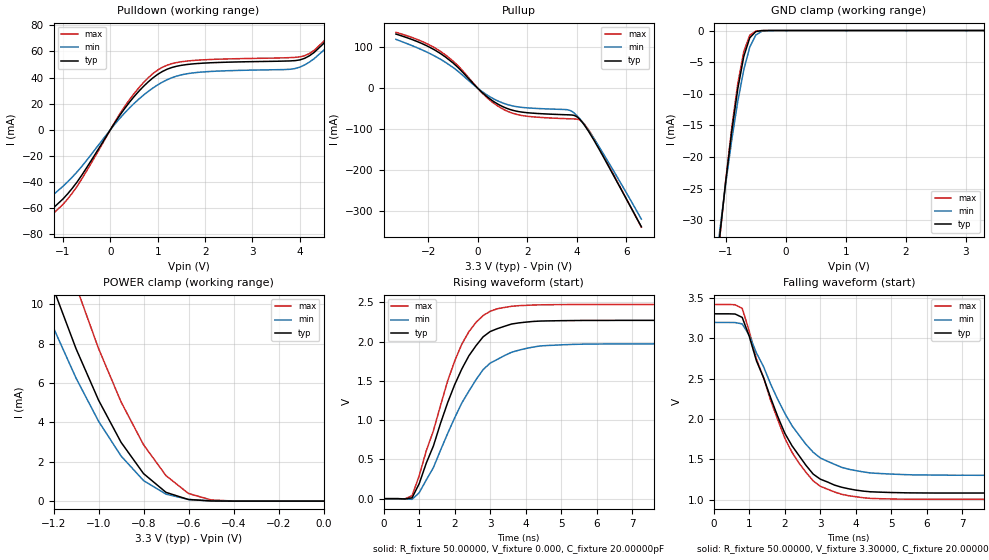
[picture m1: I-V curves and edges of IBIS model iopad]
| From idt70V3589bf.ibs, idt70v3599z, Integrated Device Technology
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|in   NC   NC
|oe   NC   NC
|   Model iopad
[Model]   iopad
Model_type   I/O
Polarity   Non-Inverting
Enable   Active-Low
Vinl =  0.80000V
Vinh =  2.00000V
Vmeas =  1.50000V
C_comp   4.50000pF   NA   NA
[Temperature Range]   25.00000   100.00000   0.000
[Voltage Range]   3.30000V   3.15000V   3.45000V
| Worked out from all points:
|   slope of the pulldown table from 0 to 0.495 V, typ, clamps not added: 19.7 ohm
|   slope of the pullup table from 0 to 0.495 V, typ, clamps not added: 18.9 ohm
|   GND clamp passes 1 mA (typ) near -0.58 V on its own axis
|   POWER clamp passes 1 mA (typ) near -0.76 V on its own axis
|   rising waveform, R_fixture 50.00000, V_fixture 0.000, C_fixture 20.00000pF: 20-80 % time 1.19ns typ, 1.3ns min, 1.09ns max; typ from 0 V to 2.27 V
|   falling waveform, R_fixture 50.00000, V_fixture 3.30000, C_fixture 20.00000pF: 20-80 % time 1.32ns typ, 1.4ns min, 1.26ns max; typ from 3.3 V to 1.08 V
[Pulldown]
| voltage   I(typ)   I(min)   I(max)
-3.3V     -84.5mA    -82mA      -85.8mA
-2.1V     -78mA      -70.6mA    -80.7mA
-1.3V     -63.18mA   -52.81mA   -67.45mA
-700mV    -39.93mA   -32.22mA   -43.24mA
500mV     25.36mA    20.13mA    27.67mA
1.2V      46.44mA    38.37mA    49.52mA
1.8V      50.66mA    43.81mA    53.24mA
4V        53.54mA    47.99mA    55.87mA
4.5V      66.02mA    60.79mA    67.62mA
4.7V      75.09mA    68.69mA    77.1mA
4.9V      86.42mA    78.18mA    89.18mA
6.6V      303mA      251.6mA    324.1mA
[Pullup]
| voltage   I(typ)   I(min)   I(max)
-3.3V     132.5mA    119.5mA    136.7mA
-2.1V     105mA      89.78mA    110.5mA
-1.3V     76.36mA    63.36mA    81.44mA
-700mV    44.89mA    36.5mA     48.95mA
300mV     -16.89mA   -13.47mA   -18.88mA
1.1V      -47.4mA    -37.98mA   -53.5mA
1.9V      -59.21mA   -47.5mA    -67.72mA
3.6V      -64.89mA   -52.42mA   -74.44mA
4V        -69.72mA   -66.87mA   -75.53mA
4.3V      -89.89mA   -88.74mA   -87.48mA
4.7V      -128.3mA   -124.3mA   -124.1mA
6.6V      -338.7mA   -320mA     -339.6mA
[GND_clamp]
| voltage   I(typ)   I(min)   I(max)
-3.3V     -268.4mA   -247.6mA   -275.9mA
-1.1V     -32.46mA   -31.63mA   -32.77mA
-1V       -23.79mA   -24.13mA   -23.62mA
-900mV    -15.93mA   -17.27mA   -15.36mA
-800mV    -9.216mA   -11.21mA   -8.395mA
-700mV    -4.104mA   -6.21mA    -3.33mA
-600mV    -1.149mA   -2.618mA   -751.2uA
-500mV    -171.6uA   -715.3uA   -87.25uA
-400mV    -15.64uA   -119.9uA   -6.065uA
-300mV    -924.1nA   -14.35uA   -255.3nA
3.3V      620.9pA    59.77nA    69.31pA
[POWER_clamp]
| voltage   I(typ)   I(min)   I(max)
-3.3V     130.9mA    110mA      146.6mA
-1.3V     14.2mA     11.66mA    18.56mA
-1.2V     10.79mA    8.802mA    14.55mA
-1.1V     7.751mA    6.256mA    10.94mA
-1V       5.137mA    4.064mA    7.76mA
-900mV    2.994mA    2.297mA    5.049mA
-800mV    1.4mA      1.046mA    2.868mA
-700mV    444.9uA    353.9uA    1.294mA
-600mV    80.76uA    86.94uA    387.4uA
-500mV    9.37uA     15.85uA    61.9uA
-400mV    813.2nA    2.325uA    5.81uA
0V        620.9pA    47.22nA    96.23pA
[Ramp]
| variable   typ   min   max
dV/dt_r   1.36320/0.50060n   1.18380/0.60750n   1.48500/0.42662n
dV/dt_f   1.33080/0.35668n   1.15980/0.45678n   1.42440/0.34997n
R_load = 50.00000
[Rising Waveform]
R_fixture = 50.00000
V_fixture = 0.000
C_fixture = 20.00000pF
R_dut = 100.00000m
L_dut = 4.00000nH
C_dut = 0.64000pF
| time   V(typ)   V(min)   V(max)
0s        0V         0V         0V
800ps     10.63mV    -8.365mV   38.52mV
1ns       190.2mV    75.06mV    291.4mV
1.4ns     670mV      395.2mV    863.9mV
1.8ns     1.22V      828.1mV    1.496V
2.2ns     1.651V     1.218V     1.967V
2.6ns     1.948V     1.514V     2.244V
3ns       2.128V     1.726V     2.386V
4.4ns     2.261V     1.944V     2.467V
10ns      2.27V      1.971V     2.472V
[Falling Waveform]
R_fixture = 50.00000
V_fixture = 3.30000
C_fixture = 20.00000pF
R_dut = 100.00000m
L_dut = 4.00000nH
C_dut = 0.64000pF
| time   V(typ)   V(min)   V(max)
0s        3.3V       3.193V     3.415V
800ps     3.256V     3.175V     3.367V
1ns       3.02V      3.036V     3.083V
1.2ns     2.72V      2.817V     2.743V
2ns       1.823V     2.07V      1.762V
2.4ns     1.547V     1.8V       1.454V
3ns       1.256V     1.518V     1.168V
3.6ns     1.157V     1.403V     1.069V
4.4ns     1.101V     1.333V     1.019V
10ns      1.085V     1.304V     1.007V
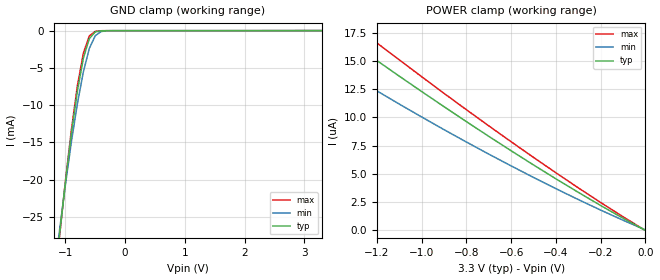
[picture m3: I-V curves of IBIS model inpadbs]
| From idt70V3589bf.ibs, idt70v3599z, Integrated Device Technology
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|   Model inpadbs
[Model]   inpadbs
Model_type   Input
Vinl =  0.80000V
Vinh =  2.00000V
C_comp   4.50000pF   NA   NA
[Temperature Range]   25.00000   100.00000   0.000
[Voltage Range]   3.30000V   3.15000V   3.45000V
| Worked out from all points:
|   GND clamp passes 1 mA (typ) near -0.59 V on its own axis
[GND_clamp]
| voltage   I(typ)   I(min)   I(max)
-3.3V     -213.7mA   -198.9mA   -219mA
-1.1V     -27.44mA   -26.83mA   -27.65mA
-1V       -20.29mA   -20.62mA   -20.13mA
-900mV    -13.76mA   -14.89mA   -13.27mA
-800mV    -8.098mA   -9.797mA   -7.398mA
-700mV    -3.702mA   -5.527mA   -3.024mA
-600mV    -1.073mA   -2.393mA   -711.1uA
-500mV    -172.4uA   -675.5uA   -95.13uA
-400mV    -25.71uA   -121.6uA   -18.58uA
-300mV    -11.69uA   -22.03uA   -13.03uA
3.3V      619.5pA    1.349uA    -1.719uA
[POWER_clamp]
| voltage   I(typ)   I(min)   I(max)
-3.3V     51.42uA    48.66uA    54.89uA
-1.7V     22.27uA    18.66uA    24.4uA
-1.6V     20.78uA    17.33uA    22.8uA
-1.4V     17.86uA    14.78uA    19.65uA
-1.3V     16.43uA    13.55uA    18.11uA
-1.2V     15.03uA    12.35uA    16.59uA
-900mV    10.95uA    8.918uA    12.13uA
-600mV    7.049uA    5.71uA     7.847uA
-300mV    3.372uA    2.735uA    3.771uA
0V        621.7pA    47nA       96.04pA
